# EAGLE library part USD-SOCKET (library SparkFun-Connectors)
microSD Socket Push-push type uSD socket. Schematic element and footprint production proven. Spark Fun Electronics SKU : PRT-00127. tDoc lines correctly indicate media card edge positions when inserting (unlocked, locked, depressed). NOTE: CD1 and CD2 are connected internally

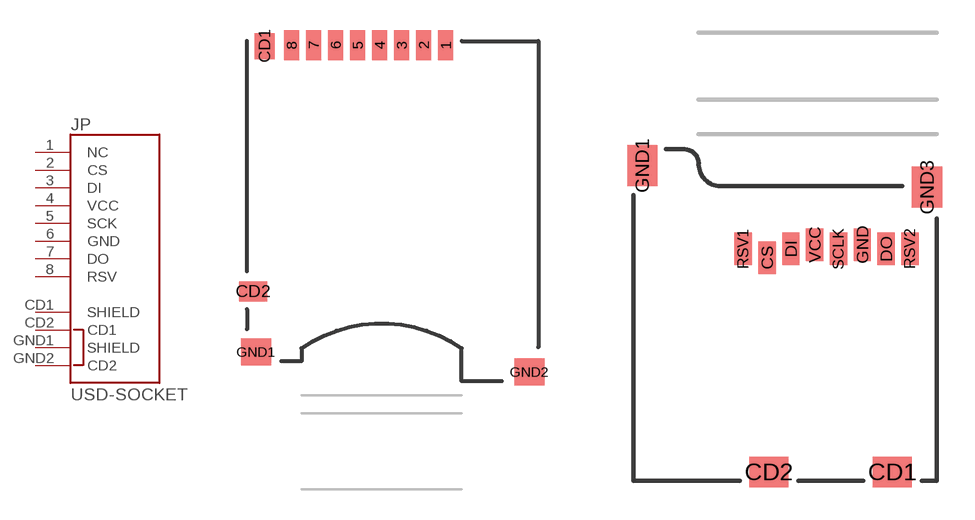
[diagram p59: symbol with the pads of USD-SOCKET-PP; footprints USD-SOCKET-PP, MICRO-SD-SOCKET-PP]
Designator prefix JP

## USD-SOCKETUSD  [USD-SOCKET-PP]
1  NC
2  CS
3  DI
4  VCC
5  SCK
6  GND
7  DO
8  RSV
CD1  SHIELD
CD2  CD1
GND1  SHIELD
GND2  CD2

## USD-SOCKETNEW (PROD_ID: CONN-07820)  [MICRO-SD-SOCKET-PP]
CD1  CD1
CD2  CD2
CS  CS
DI  DI
DO  DO
GND  GND
GND1  SHIELD
GND3  SHIELD
RSV1  NC
RSV2  RSV
SCLK  SCK
VCC  VCC

## USD-SOCKET (PROD_ID: CONN-07820)  [MICROSD_1:1]
1  NC
2  CS
3  DI
4  VCC
5  SCK
6  GND
7  DO
8  RSV
CD1  CD1
CD2  CD2
GND1  SHIELD
GND3  SHIELD

## Footprint USD-SOCKET-PP (pad centres in mm)
OLD Production Socket. DO NOT USE for production boards.
smd 0.75 x 1.5: 1 3.2,16.8; 2 2.1,16.8; 3 1,16.8; 4 -0.1,16.8; 5 -1.2,16.8; 6 -2.3,16.8; 7 -3.4,16.8; 8 -4.5,16.8
smd 1 x 1.3: CD1 -5.85,16.75
smd 1.4 x 1: CD2 -6.425,4.5
smd 1.5 x 1.35: GND1 -6.275,1.475; GND2 7.375,0.475

## Footprint MICRO-SD-SOCKET-PP (pad centres in mm)
smd 1.8 x 1.4: CD1 -2.05,0.4; CD2 -7.75,0.4
smd 0.8 x 1.5: CS -7.84,10.3; DI -6.74,10.7; DO -2.34,10.7; GND -3.44,10.9; RSV1 -8.94,10.7; RSV2 -1.24,10.7; SCLK -4.54,10.7; VCC -5.64,10.9
smd 1.4 x 1.9: GND1 -13.6,14.55; GND3 -0.45,13.55

## Footprint MICROSD_1:1 (pad centres in mm)
smd 0.8 x 1.5: 1 5.096,10.919; 2 6.218,10.519; 3 7.274,10.853; 4 8.367,10.982; 5 9.421,10.828; 6 10.539,10.973; 7 11.648,10.819; 8 12.721,10.819
smd 1.8 x 1.4: CD1 11.92,0.4; CD2 6.22,0.4
smd 1.4 x 1.9: GND1 0.497,14.55; GND3 13.52,13.55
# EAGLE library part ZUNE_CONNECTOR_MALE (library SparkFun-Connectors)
Male connector for the Zune media player. UNPROVEN FOOTPRINT! This connector must be used only with a 1.2mm PCB thickness.

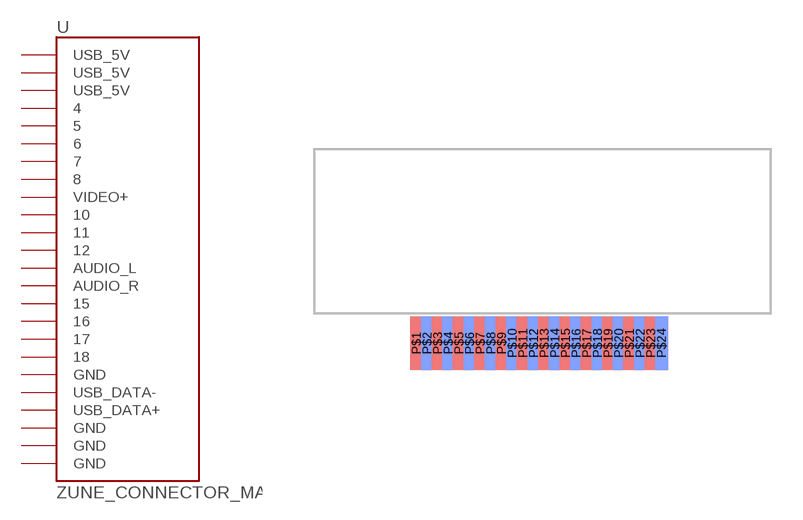
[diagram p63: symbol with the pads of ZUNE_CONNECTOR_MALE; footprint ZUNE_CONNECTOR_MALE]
Designator prefix -

## ZUNE_CONNECTOR_MALE  [ZUNE_CONNECTOR_MALE]
P$1  USB_5V
P$2  USB_5V
P$3  USB_5V
P$4  4
P$5  5
P$6  6
P$7  7
P$8  8
P$9  VIDEO+
P$10  10
P$11  11
P$12  12
P$13  AUDIO_L
P$14  AUDIO_R
P$15  15
P$16  16
P$17  17
P$18  18
P$19  GND
P$20  USB_DATA-
P$21  USB_DATA+
P$22  GND
P$23  GND
P$24  GND

## Footprint ZUNE_CONNECTOR_MALE (pad centres in mm)
smd 0.6 x 2.5: P$1 0,0; P$3 1,0; P$5 2,0; P$7 3,0; P$9 4,0; P$11 5,0; P$13 6,0; P$15 7,0; P$17 8,0; P$19 9,0; P$21 10,0; P$23 11,0
smd 0.6 x 2.5 bottom: P$2 0.5,0; P$4 1.5,0; P$6 2.5,0; P$8 3.5,0; P$10 4.5,0; P$12 5.5,0; P$14 6.5,0; P$16 7.5,0; P$18 8.5,0; P$20 9.5,0; P$22 10.5,0; P$24 11.5,0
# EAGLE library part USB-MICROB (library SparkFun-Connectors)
RED_PASTE version has 70% paste area under D+ D- USBID pins for applications where those pins aren't required, to reduce the likelihood of bridges.

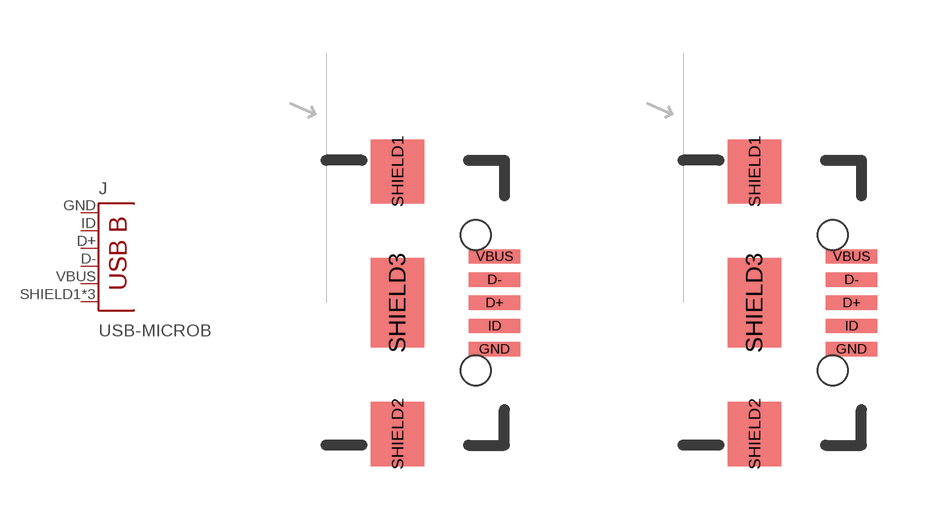
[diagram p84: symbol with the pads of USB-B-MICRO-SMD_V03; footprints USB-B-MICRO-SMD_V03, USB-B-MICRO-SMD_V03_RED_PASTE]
Designator prefix J

## USB-MICROB" (PROD_ID: CONN-11752)  [USB-B-MICRO-SMD_V03]
D+  D+
D-  D-
GND  GND
ID  USBID
SHIELD1  SHIELD
SHIELD2  SHIELD
SHIELD3  SHIELD
VBUS  VBUS

## USB-MICROBREDUCED_PASTE  [USB-B-MICRO-SMD_V03_RED_PASTE]
Pads as for USB-B-MICRO-SMD_V03

## Footprint USB-B-MICRO-SMD_V03 (pad centres in mm)
smd 1.45 x 0.4: D+ 2.725,0; D- 2.725,0.65; GND 2.725,-1.3; ID 2.725,-0.65; VBUS 2.725,1.3
smd 1.5 x 1.8: SHIELD1 0,3.685; SHIELD2 0,-3.685
smd 1.5 x 2.5: SHIELD3 0,0
hole 0.85 at 2.2,1.9
hole 0.85 at 2.2,-1.9

## Footprint USB-B-MICRO-SMD_V03_RED_PASTE (pad centres in mm)
smd 1.45 x 0.4: D+ 2.725,0; D- 2.725,0.65; GND 2.725,-1.3; ID 2.725,-0.65; VBUS 2.725,1.3
smd 1.5 x 1.8: SHIELD1 0,3.685; SHIELD2 0,-3.685
smd 1.5 x 2.5: SHIELD3 0,0
hole 0.85 at 2.2,1.9
hole 0.85 at 2.2,-1.9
